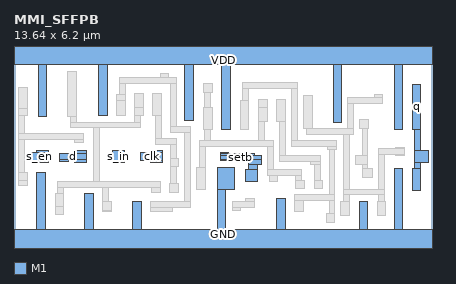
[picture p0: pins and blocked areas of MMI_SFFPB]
MACRO MMI_SFFPB
	CLASS CORE ;
	FOREIGN MMI_SFFPB 0 0 ;
	SIZE 13.64 BY 6.2 ;
	SYMMETRY X Y ;
	SITE CORE1 ;
	PIN d
		DIRECTION input ;
		USE SIGNAL ;
		PORT
			LAYER M1 ;
			RECT 1.5 2.88 1.78 2.9 ;
			LAYER M1 ;
			RECT 1.98 2.88 2.36 2.98 ;
			LAYER M1 ;
			RECT 1.5 2.685 2.36 2.88 ;
			LAYER M1 ;
			RECT 1.5 2.62 1.78 2.685 ;
			LAYER M1 ;
			RECT 1.98 2.6 2.36 2.685 ;
		END
		AntennaGateArea 0.3465 ;
	END d
	PIN GND
		DIRECTION inout ;
		USE GROUND ;
		PORT
			LAYER M1 ;
			RECT 0.75 0.42 1.03 2.28 ;
			LAYER M1 ;
			RECT 6.625 1.72 7.205 2.42 ;
			LAYER M1 ;
			RECT 2.3 0.42 2.58 1.585 ;
			LAYER M1 ;
			RECT 3.865 0.42 4.145 1.315 ;
			LAYER M1 ;
			RECT 6.625 0.42 6.91 1.72 ;
			LAYER M1 ;
			RECT 8.57 0.42 8.85 1.43 ;
			LAYER M1 ;
			RECT 11.26 0.42 11.54 1.33 ;
			LAYER M1 ;
			RECT 12.41 0.42 12.69 2.39 ;
			LAYER M1 ;
			RECT 0 -0.42 13.645 0.42 ;
		END
	END GND
	PIN q
		DIRECTION output ;
		USE SIGNAL ;
		PORT
			LAYER M1 ;
			RECT 13 3.68 13.28 5.15 ;
			LAYER M1 ;
			RECT 13.075 2.98 13.27 3.68 ;
			LAYER M1 ;
			RECT 13.075 2.6 13.52 2.98 ;
			LAYER M1 ;
			RECT 13.075 2.39 13.27 2.6 ;
			LAYER M1 ;
			RECT 13 1.69 13.28 2.39 ;
		END
		AntennaDiffArea 0.91245 ;
	END q
	PIN s_in
		DIRECTION input ;
		USE SIGNAL ;
		PORT
			LAYER M1 ;
			RECT 3.22 2.6 3.6 2.98 ;
		END
		AntennaGateArea 0.17325 ;
	END s_in
	PIN s_en
		DIRECTION input ;
		USE SIGNAL ;
		PORT
			LAYER M1 ;
			RECT 0.74 2.93 1.12 2.98 ;
			LAYER M1 ;
			RECT 0.555 2.65 1.12 2.93 ;
			LAYER M1 ;
			RECT 0.74 2.6 1.12 2.65 ;
		END
		AntennaGateArea 0.51525 ;
	END s_en
	PIN VDD
		DIRECTION inout ;
		USE POWER ;
		PORT
			LAYER M1 ;
			RECT 0 5.78 13.645 6.62 ;
			LAYER M1 ;
			RECT 0.795 4.11 1.075 5.78 ;
			LAYER M1 ;
			RECT 2.755 4.115 3.035 5.78 ;
			LAYER M1 ;
			RECT 5.575 3.96 5.855 5.78 ;
			LAYER M1 ;
			RECT 6.775 3.675 7.055 5.78 ;
			LAYER M1 ;
			RECT 10.415 3.9 10.695 5.78 ;
			LAYER M1 ;
			RECT 12.41 3.68 12.69 5.78 ;
		END
	END VDD
	PIN setb
		DIRECTION input ;
		USE SIGNAL ;
		PORT
			LAYER M1 ;
			RECT 6.73 2.88 7.01 2.93 ;
			LAYER M1 ;
			RECT 6.73 2.815 7.84 2.88 ;
			LAYER M1 ;
			RECT 6.73 2.685 8.065 2.815 ;
			LAYER M1 ;
			RECT 6.73 2.65 7.01 2.685 ;
			LAYER M1 ;
			RECT 7.645 2.535 8.065 2.685 ;
			LAYER M1 ;
			RECT 7.645 2.36 7.94 2.535 ;
			LAYER M1 ;
			RECT 7.565 1.98 7.94 2.36 ;
		END
		AntennaGateArea 0.4575 ;
	END setb
	PIN clk
		DIRECTION input ;
		USE CLOCK ;
		PORT
			LAYER M1 ;
			RECT 4.46 2.93 4.84 2.98 ;
			LAYER M1 ;
			RECT 4.15 2.925 4.84 2.93 ;
			LAYER M1 ;
			RECT 4.14 2.645 4.84 2.925 ;
			LAYER M1 ;
			RECT 4.46 2.6 4.84 2.645 ;
		END
		AntennaGateArea 0.44625 ;
	END clk
	OBS
		LAYER M1 ;
		RECT 0.16 4.35 0.44 5.05 ;
		LAYER M1 ;
		RECT 0.15 4.115 0.44 4.35 ;
		LAYER M1 ;
		RECT 0.15 3.525 0.345 4.115 ;
		LAYER M1 ;
		RECT 1.755 4.11 2.035 5.58 ;
		LAYER M1 ;
		RECT 4.77 5.365 5.05 5.49 ;
		LAYER M1 ;
		RECT 3.445 5.175 5.295 5.365 ;
		LAYER M1 ;
		RECT 3.445 4.815 3.635 5.175 ;
		LAYER M1 ;
		RECT 3.345 4.615 3.635 4.815 ;
		LAYER M1 ;
		RECT 3.345 4.115 3.625 4.615 ;
		LAYER M1 ;
		RECT 3.945 4.375 4.225 4.835 ;
		LAYER M1 ;
		RECT 3.94 4.135 4.225 4.375 ;
		LAYER M1 ;
		RECT 4.535 4.135 4.815 4.835 ;
		LAYER M1 ;
		RECT 1.84 3.915 2.035 4.11 ;
		LAYER M1 ;
		RECT 3.94 3.915 4.13 4.135 ;
		LAYER M1 ;
		RECT 1.84 3.725 4.13 3.915 ;
		LAYER M1 ;
		RECT 0.15 3.335 2.27 3.525 ;
		LAYER M1 ;
		RECT 0.15 2.28 0.345 3.335 ;
		LAYER M1 ;
		RECT 1.99 3.245 2.27 3.335 ;
		LAYER M1 ;
		RECT 0.15 2 0.44 2.28 ;
		LAYER M1 ;
		RECT 0.16 1.845 0.44 2 ;
		LAYER M1 ;
		RECT 2.58 1.985 2.775 3.725 ;
		LAYER M1 ;
		RECT 4.625 3.37 4.815 4.135 ;
		LAYER M1 ;
		RECT 5.105 3.76 5.295 5.175 ;
		LAYER M1 ;
		RECT 6.185 4.885 6.465 5.165 ;
		LAYER M1 ;
		RECT 6.23 4.375 6.425 4.885 ;
		LAYER M1 ;
		RECT 5.105 3.57 5.765 3.76 ;
		LAYER M1 ;
		RECT 6.185 3.675 6.465 4.375 ;
		LAYER M1 ;
		RECT 7.465 5.01 9.245 5.205 ;
		LAYER M1 ;
		RECT 7.465 4.61 7.66 5.01 ;
		LAYER M1 ;
		RECT 7.38 3.675 7.66 4.61 ;
		LAYER M1 ;
		RECT 7.98 4.375 8.26 4.635 ;
		LAYER M1 ;
		RECT 7.975 3.935 8.26 4.375 ;
		LAYER M1 ;
		RECT 8.57 3.935 8.85 4.635 ;
		LAYER M1 ;
		RECT 4.625 3.18 5.31 3.37 ;
		LAYER M1 ;
		RECT 5.12 2.735 5.31 3.18 ;
		LAYER M1 ;
		RECT 5.095 2.455 5.375 2.735 ;
		LAYER M1 ;
		RECT 1.435 1.98 2.775 1.985 ;
		LAYER M1 ;
		RECT 1.435 1.79 4.78 1.98 ;
		LAYER M1 ;
		RECT 5.12 1.91 5.31 2.455 ;
		LAYER M1 ;
		RECT 1.435 1.585 1.625 1.79 ;
		LAYER M1 ;
		RECT 2.58 1.785 4.78 1.79 ;
		LAYER M1 ;
		RECT 1.34 1.145 1.625 1.585 ;
		LAYER M1 ;
		RECT 1.34 0.885 1.62 1.145 ;
		LAYER M1 ;
		RECT 2.89 1.315 3.085 1.785 ;
		LAYER M1 ;
		RECT 4.5 1.63 4.78 1.785 ;
		LAYER M1 ;
		RECT 5.09 1.63 5.37 1.91 ;
		LAYER M1 ;
		RECT 4.895 1.315 5.175 1.32 ;
		LAYER M1 ;
		RECT 5.575 1.315 5.765 3.57 ;
		LAYER M1 ;
		RECT 6.23 3.325 6.425 3.675 ;
		LAYER M1 ;
		RECT 7.975 3.325 8.165 3.935 ;
		LAYER M1 ;
		RECT 6.05 3.13 8.455 3.325 ;
		LAYER M1 ;
		RECT 6.05 2.42 6.245 3.13 ;
		LAYER M1 ;
		RECT 5.965 1.72 6.245 2.42 ;
		LAYER M1 ;
		RECT 8.265 2.35 8.455 3.13 ;
		LAYER M1 ;
		RECT 8.655 2.81 8.85 3.935 ;
		LAYER M1 ;
		RECT 9.055 3.305 9.245 5.01 ;
		LAYER M1 ;
		RECT 9.445 3.705 9.725 4.765 ;
		LAYER M1 ;
		RECT 11.76 4.715 12.04 4.805 ;
		LAYER M1 ;
		RECT 10.895 4.525 12.04 4.715 ;
		LAYER M1 ;
		RECT 9.53 3.695 9.725 3.705 ;
		LAYER M1 ;
		RECT 10.895 3.695 11.085 4.525 ;
		LAYER M1 ;
		RECT 11.285 3.705 11.565 3.985 ;
		LAYER M1 ;
		RECT 9.53 3.505 11.085 3.695 ;
		LAYER M1 ;
		RECT 9.055 3.115 10.525 3.305 ;
		LAYER M1 ;
		RECT 10.245 3.025 10.525 3.115 ;
		LAYER M1 ;
		RECT 9.675 2.81 9.955 2.825 ;
		LAYER M1 ;
		RECT 8.655 2.62 9.995 2.81 ;
		LAYER M1 ;
		RECT 9.675 2.545 9.995 2.62 ;
		LAYER M1 ;
		RECT 8.265 2.16 9.39 2.35 ;
		LAYER M1 ;
		RECT 8.325 1.965 8.605 2.16 ;
		LAYER M1 ;
		RECT 9.195 2.02 9.39 2.16 ;
		LAYER M1 ;
		RECT 9.8 2.02 9.995 2.545 ;
		LAYER M1 ;
		RECT 9.195 1.755 9.485 2.02 ;
		LAYER M1 ;
		RECT 9.205 1.74 9.485 1.755 ;
		LAYER M1 ;
		RECT 9.795 1.74 10.075 2.02 ;
		LAYER M1 ;
		RECT 2.89 1.03 3.18 1.315 ;
		LAYER M1 ;
		RECT 2.9 1 3.18 1.03 ;
		LAYER M1 ;
		RECT 4.455 1.125 5.765 1.315 ;
		LAYER M1 ;
		RECT 4.455 1 5.18 1.125 ;
		LAYER M1 ;
		RECT 4.5 0.995 5.18 1 ;
		LAYER M1 ;
		RECT 10.28 1.54 10.47 3.025 ;
		LAYER M1 ;
		RECT 7.56 1.31 7.84 1.425 ;
		LAYER M1 ;
		RECT 7.125 1.12 7.85 1.31 ;
		LAYER M1 ;
		RECT 7.125 1.03 7.405 1.12 ;
		LAYER M1 ;
		RECT 9.16 1.345 10.47 1.54 ;
		LAYER M1 ;
		RECT 9.16 0.995 9.44 1.345 ;
		LAYER M1 ;
		RECT 10.28 0.925 10.47 1.345 ;
		LAYER M1 ;
		RECT 10.755 1.725 10.95 3.505 ;
		LAYER M1 ;
		RECT 11.36 2.825 11.55 3.705 ;
		LAYER M1 ;
		RECT 12.465 3.05 12.745 3.1 ;
		LAYER M1 ;
		RECT 11.15 2.545 11.55 2.825 ;
		LAYER M1 ;
		RECT 11.36 2.39 11.55 2.545 ;
		LAYER M1 ;
		RECT 11.9 2.86 12.745 3.05 ;
		LAYER M1 ;
		RECT 11.36 2.11 11.69 2.39 ;
		LAYER M1 ;
		RECT 11.9 1.725 12.095 2.86 ;
		LAYER M1 ;
		RECT 12.465 2.82 12.745 2.86 ;
		LAYER M1 ;
		RECT 10.755 1.535 12.095 1.725 ;
		LAYER M1 ;
		RECT 10.755 1.33 10.95 1.535 ;
		LAYER M1 ;
		RECT 11.9 1.33 12.095 1.535 ;
		LAYER M1 ;
		RECT 10.19 0.645 10.47 0.925 ;
		LAYER M1 ;
		RECT 10.67 0.88 10.95 1.33 ;
		LAYER M1 ;
		RECT 11.85 0.88 12.13 1.33 ;
	END
END MMI_SFFPB
